VERSION 5.7 ;
BUSBITCHARS "[]" ;
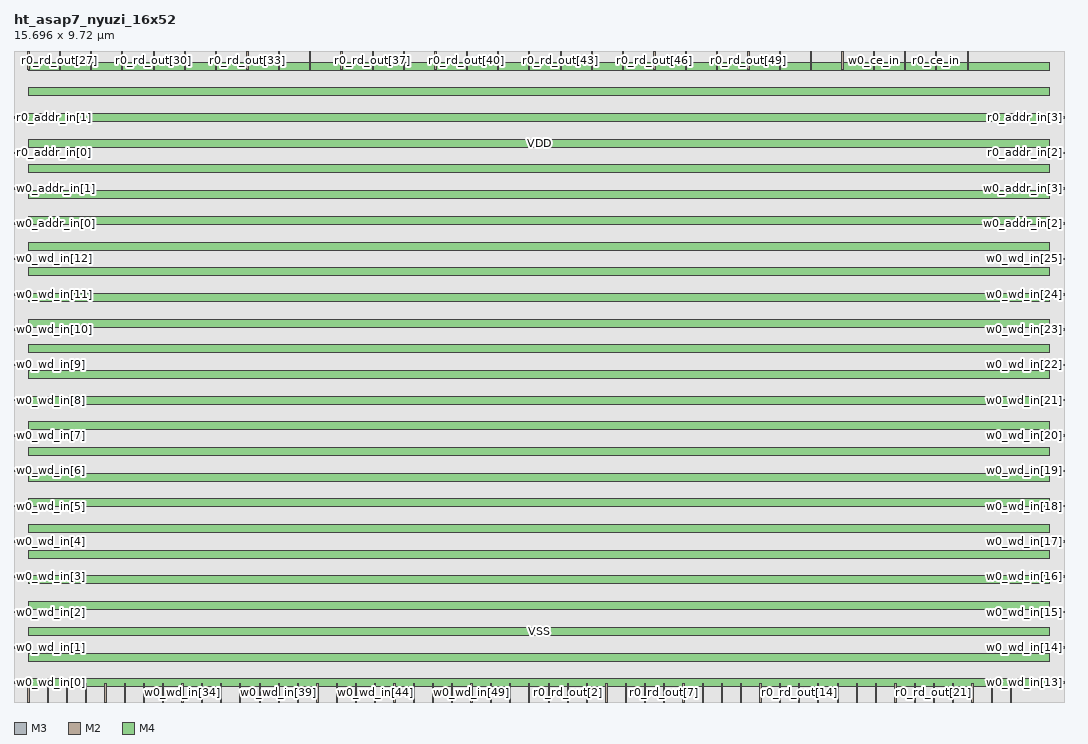
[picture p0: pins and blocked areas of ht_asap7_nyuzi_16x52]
MACRO ht_asap7_nyuzi_16x52
  FOREIGN ht_asap7_nyuzi_16x52 0 0 ;
  SYMMETRY X Y R90 ;
  SIZE 15.696 BY 9.720 ;
  CLASS BLOCK ;
  PIN w0_wd_in[0]
    DIRECTION INPUT ;
    USE SIGNAL ;
    SHAPE ABUTMENT ;
    PORT
      LAYER M3 ;
      RECT 0.000 0.276 0.072 0.300 ;
    END
  END w0_wd_in[0]
  PIN w0_wd_in[1]
    DIRECTION INPUT ;
    USE SIGNAL ;
    SHAPE ABUTMENT ;
    PORT
      LAYER M3 ;
      RECT 0.000 0.804 0.072 0.828 ;
    END
  END w0_wd_in[1]
  PIN w0_wd_in[2]
    DIRECTION INPUT ;
    USE SIGNAL ;
    SHAPE ABUTMENT ;
    PORT
      LAYER M3 ;
      RECT 0.000 1.332 0.072 1.356 ;
    END
  END w0_wd_in[2]
  PIN w0_wd_in[3]
    DIRECTION INPUT ;
    USE SIGNAL ;
    SHAPE ABUTMENT ;
    PORT
      LAYER M3 ;
      RECT 0.000 1.860 0.072 1.884 ;
    END
  END w0_wd_in[3]
  PIN w0_wd_in[4]
    DIRECTION INPUT ;
    USE SIGNAL ;
    SHAPE ABUTMENT ;
    PORT
      LAYER M3 ;
      RECT 0.000 2.388 0.072 2.412 ;
    END
  END w0_wd_in[4]
  PIN w0_wd_in[5]
    DIRECTION INPUT ;
    USE SIGNAL ;
    SHAPE ABUTMENT ;
    PORT
      LAYER M3 ;
      RECT 0.000 2.916 0.072 2.940 ;
    END
  END w0_wd_in[5]
  PIN w0_wd_in[6]
    DIRECTION INPUT ;
    USE SIGNAL ;
    SHAPE ABUTMENT ;
    PORT
      LAYER M3 ;
      RECT 0.000 3.444 0.072 3.468 ;
    END
  END w0_wd_in[6]
  PIN w0_wd_in[7]
    DIRECTION INPUT ;
    USE SIGNAL ;
    SHAPE ABUTMENT ;
    PORT
      LAYER M3 ;
      RECT 0.000 3.972 0.072 3.996 ;
    END
  END w0_wd_in[7]
  PIN w0_wd_in[8]
    DIRECTION INPUT ;
    USE SIGNAL ;
    SHAPE ABUTMENT ;
    PORT
      LAYER M3 ;
      RECT 0.000 4.500 0.072 4.524 ;
    END
  END w0_wd_in[8]
  PIN w0_wd_in[9]
    DIRECTION INPUT ;
    USE SIGNAL ;
    SHAPE ABUTMENT ;
    PORT
      LAYER M3 ;
      RECT 0.000 5.028 0.072 5.052 ;
    END
  END w0_wd_in[9]
  PIN w0_wd_in[10]
    DIRECTION INPUT ;
    USE SIGNAL ;
    SHAPE ABUTMENT ;
    PORT
      LAYER M3 ;
      RECT 0.000 5.556 0.072 5.580 ;
    END
  END w0_wd_in[10]
  PIN w0_wd_in[11]
    DIRECTION INPUT ;
    USE SIGNAL ;
    SHAPE ABUTMENT ;
    PORT
      LAYER M3 ;
      RECT 0.000 6.084 0.072 6.108 ;
    END
  END w0_wd_in[11]
  PIN w0_wd_in[12]
    DIRECTION INPUT ;
    USE SIGNAL ;
    SHAPE ABUTMENT ;
    PORT
      LAYER M3 ;
      RECT 0.000 6.612 0.072 6.636 ;
    END
  END w0_wd_in[12]
  PIN w0_wd_in[13]
    DIRECTION INPUT ;
    USE SIGNAL ;
    SHAPE ABUTMENT ;
    PORT
      LAYER M3 ;
      RECT 15.624 0.276 15.696 0.300 ;
    END
  END w0_wd_in[13]
  PIN w0_wd_in[14]
    DIRECTION INPUT ;
    USE SIGNAL ;
    SHAPE ABUTMENT ;
    PORT
      LAYER M3 ;
      RECT 15.624 0.804 15.696 0.828 ;
    END
  END w0_wd_in[14]
  PIN w0_wd_in[15]
    DIRECTION INPUT ;
    USE SIGNAL ;
    SHAPE ABUTMENT ;
    PORT
      LAYER M3 ;
      RECT 15.624 1.332 15.696 1.356 ;
    END
  END w0_wd_in[15]
  PIN w0_wd_in[16]
    DIRECTION INPUT ;
    USE SIGNAL ;
    SHAPE ABUTMENT ;
    PORT
      LAYER M3 ;
      RECT 15.624 1.860 15.696 1.884 ;
    END
  END w0_wd_in[16]
  PIN w0_wd_in[17]
    DIRECTION INPUT ;
    USE SIGNAL ;
    SHAPE ABUTMENT ;
    PORT
      LAYER M3 ;
      RECT 15.624 2.388 15.696 2.412 ;
    END
  END w0_wd_in[17]
  PIN w0_wd_in[18]
    DIRECTION INPUT ;
    USE SIGNAL ;
    SHAPE ABUTMENT ;
    PORT
      LAYER M3 ;
      RECT 15.624 2.916 15.696 2.940 ;
    END
  END w0_wd_in[18]
  PIN w0_wd_in[19]
    DIRECTION INPUT ;
    USE SIGNAL ;
    SHAPE ABUTMENT ;
    PORT
      LAYER M3 ;
      RECT 15.624 3.444 15.696 3.468 ;
    END
  END w0_wd_in[19]
  PIN w0_wd_in[20]
    DIRECTION INPUT ;
    USE SIGNAL ;
    SHAPE ABUTMENT ;
    PORT
      LAYER M3 ;
      RECT 15.624 3.972 15.696 3.996 ;
    END
  END w0_wd_in[20]
  PIN w0_wd_in[21]
    DIRECTION INPUT ;
    USE SIGNAL ;
    SHAPE ABUTMENT ;
    PORT
      LAYER M3 ;
      RECT 15.624 4.500 15.696 4.524 ;
    END
  END w0_wd_in[21]
  PIN w0_wd_in[22]
    DIRECTION INPUT ;
    USE SIGNAL ;
    SHAPE ABUTMENT ;
    PORT
      LAYER M3 ;
      RECT 15.624 5.028 15.696 5.052 ;
    END
  END w0_wd_in[22]
  PIN w0_wd_in[23]
    DIRECTION INPUT ;
    USE SIGNAL ;
    SHAPE ABUTMENT ;
    PORT
      LAYER M3 ;
      RECT 15.624 5.556 15.696 5.580 ;
    END
  END w0_wd_in[23]
  PIN w0_wd_in[24]
    DIRECTION INPUT ;
    USE SIGNAL ;
    SHAPE ABUTMENT ;
    PORT
      LAYER M3 ;
      RECT 15.624 6.084 15.696 6.108 ;
    END
  END w0_wd_in[24]
  PIN w0_wd_in[25]
    DIRECTION INPUT ;
    USE SIGNAL ;
    SHAPE ABUTMENT ;
    PORT
      LAYER M3 ;
      RECT 15.624 6.612 15.696 6.636 ;
    END
  END w0_wd_in[25]
  PIN w0_wd_in[26]
    DIRECTION INPUT ;
    USE SIGNAL ;
    SHAPE ABUTMENT ;
    PORT
      LAYER M2 ;
      RECT 0.207 0.000 0.225 0.270 ;
    END
  END w0_wd_in[26]
  PIN w0_wd_in[27]
    DIRECTION INPUT ;
    USE SIGNAL ;
    SHAPE ABUTMENT ;
    PORT
      LAYER M2 ;
      RECT 0.495 0.000 0.513 0.270 ;
    END
  END w0_wd_in[27]
  PIN w0_wd_in[28]
    DIRECTION INPUT ;
    USE SIGNAL ;
    SHAPE ABUTMENT ;
    PORT
      LAYER M2 ;
      RECT 0.783 0.000 0.801 0.270 ;
    END
  END w0_wd_in[28]
  PIN w0_wd_in[29]
    DIRECTION INPUT ;
    USE SIGNAL ;
    SHAPE ABUTMENT ;
    PORT
      LAYER M2 ;
      RECT 1.071 0.000 1.089 0.270 ;
    END
  END w0_wd_in[29]
  PIN w0_wd_in[30]
    DIRECTION INPUT ;
    USE SIGNAL ;
    SHAPE ABUTMENT ;
    PORT
      LAYER M2 ;
      RECT 1.359 0.000 1.377 0.270 ;
    END
  END w0_wd_in[30]
  PIN w0_wd_in[31]
    DIRECTION INPUT ;
    USE SIGNAL ;
    SHAPE ABUTMENT ;
    PORT
      LAYER M2 ;
      RECT 1.647 0.000 1.665 0.270 ;
    END
  END w0_wd_in[31]
  PIN w0_wd_in[32]
    DIRECTION INPUT ;
    USE SIGNAL ;
    SHAPE ABUTMENT ;
    PORT
      LAYER M2 ;
      RECT 1.935 0.000 1.953 0.270 ;
    END
  END w0_wd_in[32]
  PIN w0_wd_in[33]
    DIRECTION INPUT ;
    USE SIGNAL ;
    SHAPE ABUTMENT ;
    PORT
      LAYER M2 ;
      RECT 2.223 0.000 2.241 0.270 ;
    END
  END w0_wd_in[33]
  PIN w0_wd_in[34]
    DIRECTION INPUT ;
    USE SIGNAL ;
    SHAPE ABUTMENT ;
    PORT
      LAYER M2 ;
      RECT 2.511 0.000 2.529 0.270 ;
    END
  END w0_wd_in[34]
  PIN w0_wd_in[35]
    DIRECTION INPUT ;
    USE SIGNAL ;
    SHAPE ABUTMENT ;
    PORT
      LAYER M2 ;
      RECT 2.799 0.000 2.817 0.270 ;
    END
  END w0_wd_in[35]
  PIN w0_wd_in[36]
    DIRECTION INPUT ;
    USE SIGNAL ;
    SHAPE ABUTMENT ;
    PORT
      LAYER M2 ;
      RECT 3.087 0.000 3.105 0.270 ;
    END
  END w0_wd_in[36]
  PIN w0_wd_in[37]
    DIRECTION INPUT ;
    USE SIGNAL ;
    SHAPE ABUTMENT ;
    PORT
      LAYER M2 ;
      RECT 3.375 0.000 3.393 0.270 ;
    END
  END w0_wd_in[37]
  PIN w0_wd_in[38]
    DIRECTION INPUT ;
    USE SIGNAL ;
    SHAPE ABUTMENT ;
    PORT
      LAYER M2 ;
      RECT 3.663 0.000 3.681 0.270 ;
    END
  END w0_wd_in[38]
  PIN w0_wd_in[39]
    DIRECTION INPUT ;
    USE SIGNAL ;
    SHAPE ABUTMENT ;
    PORT
      LAYER M2 ;
      RECT 3.951 0.000 3.969 0.270 ;
    END
  END w0_wd_in[39]
  PIN w0_wd_in[40]
    DIRECTION INPUT ;
    USE SIGNAL ;
    SHAPE ABUTMENT ;
    PORT
      LAYER M2 ;
      RECT 4.239 0.000 4.257 0.270 ;
    END
  END w0_wd_in[40]
  PIN w0_wd_in[41]
    DIRECTION INPUT ;
    USE SIGNAL ;
    SHAPE ABUTMENT ;
    PORT
      LAYER M2 ;
      RECT 4.527 0.000 4.545 0.270 ;
    END
  END w0_wd_in[41]
  PIN w0_wd_in[42]
    DIRECTION INPUT ;
    USE SIGNAL ;
    SHAPE ABUTMENT ;
    PORT
      LAYER M2 ;
      RECT 4.815 0.000 4.833 0.270 ;
    END
  END w0_wd_in[42]
  PIN w0_wd_in[43]
    DIRECTION INPUT ;
    USE SIGNAL ;
    SHAPE ABUTMENT ;
    PORT
      LAYER M2 ;
      RECT 5.103 0.000 5.121 0.270 ;
    END
  END w0_wd_in[43]
  PIN w0_wd_in[44]
    DIRECTION INPUT ;
    USE SIGNAL ;
    SHAPE ABUTMENT ;
    PORT
      LAYER M2 ;
      RECT 5.391 0.000 5.409 0.270 ;
    END
  END w0_wd_in[44]
  PIN w0_wd_in[45]
    DIRECTION INPUT ;
    USE SIGNAL ;
    SHAPE ABUTMENT ;
    PORT
      LAYER M2 ;
      RECT 5.679 0.000 5.697 0.270 ;
    END
  END w0_wd_in[45]
  PIN w0_wd_in[46]
    DIRECTION INPUT ;
    USE SIGNAL ;
    SHAPE ABUTMENT ;
    PORT
      LAYER M2 ;
      RECT 5.967 0.000 5.985 0.270 ;
    END
  END w0_wd_in[46]
  PIN w0_wd_in[47]
    DIRECTION INPUT ;
    USE SIGNAL ;
    SHAPE ABUTMENT ;
    PORT
      LAYER M2 ;
      RECT 6.255 0.000 6.273 0.270 ;
    END
  END w0_wd_in[47]
  PIN w0_wd_in[48]
    DIRECTION INPUT ;
    USE SIGNAL ;
    SHAPE ABUTMENT ;
    PORT
      LAYER M2 ;
      RECT 6.543 0.000 6.561 0.270 ;
    END
  END w0_wd_in[48]
  PIN w0_wd_in[49]
    DIRECTION INPUT ;
    USE SIGNAL ;
    SHAPE ABUTMENT ;
    PORT
      LAYER M2 ;
      RECT 6.831 0.000 6.849 0.270 ;
    END
  END w0_wd_in[49]
  PIN w0_wd_in[50]
    DIRECTION INPUT ;
    USE SIGNAL ;
    SHAPE ABUTMENT ;
    PORT
      LAYER M2 ;
      RECT 7.119 0.000 7.137 0.270 ;
    END
  END w0_wd_in[50]
  PIN w0_wd_in[51]
    DIRECTION INPUT ;
    USE SIGNAL ;
    SHAPE ABUTMENT ;
    PORT
      LAYER M2 ;
      RECT 7.407 0.000 7.425 0.270 ;
    END
  END w0_wd_in[51]
  PIN r0_rd_out[0]
    DIRECTION OUTPUT ;
    USE SIGNAL ;
    SHAPE ABUTMENT ;
    PORT
      LAYER M2 ;
      RECT 7.695 0.000 7.713 0.270 ;
    END
  END r0_rd_out[0]
  PIN r0_rd_out[1]
    DIRECTION OUTPUT ;
    USE SIGNAL ;
    SHAPE ABUTMENT ;
    PORT
      LAYER M2 ;
      RECT 7.983 0.000 8.001 0.270 ;
    END
  END r0_rd_out[1]
  PIN r0_rd_out[2]
    DIRECTION OUTPUT ;
    USE SIGNAL ;
    SHAPE ABUTMENT ;
    PORT
      LAYER M2 ;
      RECT 8.271 0.000 8.289 0.270 ;
    END
  END r0_rd_out[2]
  PIN r0_rd_out[3]
    DIRECTION OUTPUT ;
    USE SIGNAL ;
    SHAPE ABUTMENT ;
    PORT
      LAYER M2 ;
      RECT 8.559 0.000 8.577 0.270 ;
    END
  END r0_rd_out[3]
  PIN r0_rd_out[4]
    DIRECTION OUTPUT ;
    USE SIGNAL ;
    SHAPE ABUTMENT ;
    PORT
      LAYER M2 ;
      RECT 8.847 0.000 8.865 0.270 ;
    END
  END r0_rd_out[4]
  PIN r0_rd_out[5]
    DIRECTION OUTPUT ;
    USE SIGNAL ;
    SHAPE ABUTMENT ;
    PORT
      LAYER M2 ;
      RECT 9.135 0.000 9.153 0.270 ;
    END
  END r0_rd_out[5]
  PIN r0_rd_out[6]
    DIRECTION OUTPUT ;
    USE SIGNAL ;
    SHAPE ABUTMENT ;
    PORT
      LAYER M2 ;
      RECT 9.423 0.000 9.441 0.270 ;
    END
  END r0_rd_out[6]
  PIN r0_rd_out[7]
    DIRECTION OUTPUT ;
    USE SIGNAL ;
    SHAPE ABUTMENT ;
    PORT
      LAYER M2 ;
      RECT 9.711 0.000 9.729 0.270 ;
    END
  END r0_rd_out[7]
  PIN r0_rd_out[8]
    DIRECTION OUTPUT ;
    USE SIGNAL ;
    SHAPE ABUTMENT ;
    PORT
      LAYER M2 ;
      RECT 9.999 0.000 10.017 0.270 ;
    END
  END r0_rd_out[8]
  PIN r0_rd_out[9]
    DIRECTION OUTPUT ;
    USE SIGNAL ;
    SHAPE ABUTMENT ;
    PORT
      LAYER M2 ;
      RECT 10.287 0.000 10.305 0.270 ;
    END
  END r0_rd_out[9]
  PIN r0_rd_out[10]
    DIRECTION OUTPUT ;
    USE SIGNAL ;
    SHAPE ABUTMENT ;
    PORT
      LAYER M2 ;
      RECT 10.575 0.000 10.593 0.270 ;
    END
  END r0_rd_out[10]
  PIN r0_rd_out[11]
    DIRECTION OUTPUT ;
    USE SIGNAL ;
    SHAPE ABUTMENT ;
    PORT
      LAYER M2 ;
      RECT 10.863 0.000 10.881 0.270 ;
    END
  END r0_rd_out[11]
  PIN r0_rd_out[12]
    DIRECTION OUTPUT ;
    USE SIGNAL ;
    SHAPE ABUTMENT ;
    PORT
      LAYER M2 ;
      RECT 11.151 0.000 11.169 0.270 ;
    END
  END r0_rd_out[12]
  PIN r0_rd_out[13]
    DIRECTION OUTPUT ;
    USE SIGNAL ;
    SHAPE ABUTMENT ;
    PORT
      LAYER M2 ;
      RECT 11.439 0.000 11.457 0.270 ;
    END
  END r0_rd_out[13]
  PIN r0_rd_out[14]
    DIRECTION OUTPUT ;
    USE SIGNAL ;
    SHAPE ABUTMENT ;
    PORT
      LAYER M2 ;
      RECT 11.727 0.000 11.745 0.270 ;
    END
  END r0_rd_out[14]
  PIN r0_rd_out[15]
    DIRECTION OUTPUT ;
    USE SIGNAL ;
    SHAPE ABUTMENT ;
    PORT
      LAYER M2 ;
      RECT 12.015 0.000 12.033 0.270 ;
    END
  END r0_rd_out[15]
  PIN r0_rd_out[16]
    DIRECTION OUTPUT ;
    USE SIGNAL ;
    SHAPE ABUTMENT ;
    PORT
      LAYER M2 ;
      RECT 12.303 0.000 12.321 0.270 ;
    END
  END r0_rd_out[16]
  PIN r0_rd_out[17]
    DIRECTION OUTPUT ;
    USE SIGNAL ;
    SHAPE ABUTMENT ;
    PORT
      LAYER M2 ;
      RECT 12.591 0.000 12.609 0.270 ;
    END
  END r0_rd_out[17]
  PIN r0_rd_out[18]
    DIRECTION OUTPUT ;
    USE SIGNAL ;
    SHAPE ABUTMENT ;
    PORT
      LAYER M2 ;
      RECT 12.879 0.000 12.897 0.270 ;
    END
  END r0_rd_out[18]
  PIN r0_rd_out[19]
    DIRECTION OUTPUT ;
    USE SIGNAL ;
    SHAPE ABUTMENT ;
    PORT
      LAYER M2 ;
      RECT 13.167 0.000 13.185 0.270 ;
    END
  END r0_rd_out[19]
  PIN r0_rd_out[20]
    DIRECTION OUTPUT ;
    USE SIGNAL ;
    SHAPE ABUTMENT ;
    PORT
      LAYER M2 ;
      RECT 13.455 0.000 13.473 0.270 ;
    END
  END r0_rd_out[20]
  PIN r0_rd_out[21]
    DIRECTION OUTPUT ;
    USE SIGNAL ;
    SHAPE ABUTMENT ;
    PORT
      LAYER M2 ;
      RECT 13.743 0.000 13.761 0.270 ;
    END
  END r0_rd_out[21]
  PIN r0_rd_out[22]
    DIRECTION OUTPUT ;
    USE SIGNAL ;
    SHAPE ABUTMENT ;
    PORT
      LAYER M2 ;
      RECT 14.031 0.000 14.049 0.270 ;
    END
  END r0_rd_out[22]
  PIN r0_rd_out[23]
    DIRECTION OUTPUT ;
    USE SIGNAL ;
    SHAPE ABUTMENT ;
    PORT
      LAYER M2 ;
      RECT 14.319 0.000 14.337 0.270 ;
    END
  END r0_rd_out[23]
  PIN r0_rd_out[24]
    DIRECTION OUTPUT ;
    USE SIGNAL ;
    SHAPE ABUTMENT ;
    PORT
      LAYER M2 ;
      RECT 14.607 0.000 14.625 0.270 ;
    END
  END r0_rd_out[24]
  PIN r0_rd_out[25]
    DIRECTION OUTPUT ;
    USE SIGNAL ;
    SHAPE ABUTMENT ;
    PORT
      LAYER M2 ;
      RECT 14.895 0.000 14.913 0.270 ;
    END
  END r0_rd_out[25]
  PIN r0_rd_out[26]
    DIRECTION OUTPUT ;
    USE SIGNAL ;
    SHAPE ABUTMENT ;
    PORT
      LAYER M2 ;
      RECT 0.207 9.450 0.225 9.720 ;
    END
  END r0_rd_out[26]
  PIN r0_rd_out[27]
    DIRECTION OUTPUT ;
    USE SIGNAL ;
    SHAPE ABUTMENT ;
    PORT
      LAYER M2 ;
      RECT 0.675 9.450 0.693 9.720 ;
    END
  END r0_rd_out[27]
  PIN r0_rd_out[28]
    DIRECTION OUTPUT ;
    USE SIGNAL ;
    SHAPE ABUTMENT ;
    PORT
      LAYER M2 ;
      RECT 1.143 9.450 1.161 9.720 ;
    END
  END r0_rd_out[28]
  PIN r0_rd_out[29]
    DIRECTION OUTPUT ;
    USE SIGNAL ;
    SHAPE ABUTMENT ;
    PORT
      LAYER M2 ;
      RECT 1.611 9.450 1.629 9.720 ;
    END
  END r0_rd_out[29]
  PIN r0_rd_out[30]
    DIRECTION OUTPUT ;
    USE SIGNAL ;
    SHAPE ABUTMENT ;
    PORT
      LAYER M2 ;
      RECT 2.079 9.450 2.097 9.720 ;
    END
  END r0_rd_out[30]
  PIN r0_rd_out[31]
    DIRECTION OUTPUT ;
    USE SIGNAL ;
    SHAPE ABUTMENT ;
    PORT
      LAYER M2 ;
      RECT 2.547 9.450 2.565 9.720 ;
    END
  END r0_rd_out[31]
  PIN r0_rd_out[32]
    DIRECTION OUTPUT ;
    USE SIGNAL ;
    SHAPE ABUTMENT ;
    PORT
      LAYER M2 ;
      RECT 3.015 9.450 3.033 9.720 ;
    END
  END r0_rd_out[32]
  PIN r0_rd_out[33]
    DIRECTION OUTPUT ;
    USE SIGNAL ;
    SHAPE ABUTMENT ;
    PORT
      LAYER M2 ;
      RECT 3.483 9.450 3.501 9.720 ;
    END
  END r0_rd_out[33]
  PIN r0_rd_out[34]
    DIRECTION OUTPUT ;
    USE SIGNAL ;
    SHAPE ABUTMENT ;
    PORT
      LAYER M2 ;
      RECT 3.951 9.450 3.969 9.720 ;
    END
  END r0_rd_out[34]
  PIN r0_rd_out[35]
    DIRECTION OUTPUT ;
    USE SIGNAL ;
    SHAPE ABUTMENT ;
    PORT
      LAYER M2 ;
      RECT 4.419 9.450 4.437 9.720 ;
    END
  END r0_rd_out[35]
  PIN r0_rd_out[36]
    DIRECTION OUTPUT ;
    USE SIGNAL ;
    SHAPE ABUTMENT ;
    PORT
      LAYER M2 ;
      RECT 4.887 9.450 4.905 9.720 ;
    END
  END r0_rd_out[36]
  PIN r0_rd_out[37]
    DIRECTION OUTPUT ;
    USE SIGNAL ;
    SHAPE ABUTMENT ;
    PORT
      LAYER M2 ;
      RECT 5.355 9.450 5.373 9.720 ;
    END
  END r0_rd_out[37]
  PIN r0_rd_out[38]
    DIRECTION OUTPUT ;
    USE SIGNAL ;
    SHAPE ABUTMENT ;
    PORT
      LAYER M2 ;
      RECT 5.823 9.450 5.841 9.720 ;
    END
  END r0_rd_out[38]
  PIN r0_rd_out[39]
    DIRECTION OUTPUT ;
    USE SIGNAL ;
    SHAPE ABUTMENT ;
    PORT
      LAYER M2 ;
      RECT 6.291 9.450 6.309 9.720 ;
    END
  END r0_rd_out[39]
  PIN r0_rd_out[40]
    DIRECTION OUTPUT ;
    USE SIGNAL ;
    SHAPE ABUTMENT ;
    PORT
      LAYER M2 ;
      RECT 6.759 9.450 6.777 9.720 ;
    END
  END r0_rd_out[40]
  PIN r0_rd_out[41]
    DIRECTION OUTPUT ;
    USE SIGNAL ;
    SHAPE ABUTMENT ;
    PORT
      LAYER M2 ;
      RECT 7.227 9.450 7.245 9.720 ;
    END
  END r0_rd_out[41]
  PIN r0_rd_out[42]
    DIRECTION OUTPUT ;
    USE SIGNAL ;
    SHAPE ABUTMENT ;
    PORT
      LAYER M2 ;
      RECT 7.695 9.450 7.713 9.720 ;
    END
  END r0_rd_out[42]
  PIN r0_rd_out[43]
    DIRECTION OUTPUT ;
    USE SIGNAL ;
    SHAPE ABUTMENT ;
    PORT
      LAYER M2 ;
      RECT 8.163 9.450 8.181 9.720 ;
    END
  END r0_rd_out[43]
  PIN r0_rd_out[44]
    DIRECTION OUTPUT ;
    USE SIGNAL ;
    SHAPE ABUTMENT ;
    PORT
      LAYER M2 ;
      RECT 8.631 9.450 8.649 9.720 ;
    END
  END r0_rd_out[44]
  PIN r0_rd_out[45]
    DIRECTION OUTPUT ;
    USE SIGNAL ;
    SHAPE ABUTMENT ;
    PORT
      LAYER M2 ;
      RECT 9.099 9.450 9.117 9.720 ;
    END
  END r0_rd_out[45]
  PIN r0_rd_out[46]
    DIRECTION OUTPUT ;
    USE SIGNAL ;
    SHAPE ABUTMENT ;
    PORT
      LAYER M2 ;
      RECT 9.567 9.450 9.585 9.720 ;
    END
  END r0_rd_out[46]
  PIN r0_rd_out[47]
    DIRECTION OUTPUT ;
    USE SIGNAL ;
    SHAPE ABUTMENT ;
    PORT
      LAYER M2 ;
      RECT 10.035 9.450 10.053 9.720 ;
    END
  END r0_rd_out[47]
  PIN r0_rd_out[48]
    DIRECTION OUTPUT ;
    USE SIGNAL ;
    SHAPE ABUTMENT ;
    PORT
      LAYER M2 ;
      RECT 10.503 9.450 10.521 9.720 ;
    END
  END r0_rd_out[48]
  PIN r0_rd_out[49]
    DIRECTION OUTPUT ;
    USE SIGNAL ;
    SHAPE ABUTMENT ;
    PORT
      LAYER M2 ;
      RECT 10.971 9.450 10.989 9.720 ;
    END
  END r0_rd_out[49]
  PIN r0_rd_out[50]
    DIRECTION OUTPUT ;
    USE SIGNAL ;
    SHAPE ABUTMENT ;
    PORT
      LAYER M2 ;
      RECT 11.439 9.450 11.457 9.720 ;
    END
  END r0_rd_out[50]
  PIN r0_rd_out[51]
    DIRECTION OUTPUT ;
    USE SIGNAL ;
    SHAPE ABUTMENT ;
    PORT
      LAYER M2 ;
      RECT 11.907 9.450 11.925 9.720 ;
    END
  END r0_rd_out[51]
  PIN w0_addr_in[0]
    DIRECTION INPUT ;
    USE SIGNAL ;
    SHAPE ABUTMENT ;
    PORT
      LAYER M3 ;
      RECT 0.000 7.140 0.072 7.164 ;
    END
  END w0_addr_in[0]
  PIN w0_addr_in[1]
    DIRECTION INPUT ;
    USE SIGNAL ;
    SHAPE ABUTMENT ;
    PORT
      LAYER M3 ;
      RECT 0.000 7.668 0.072 7.692 ;
    END
  END w0_addr_in[1]
  PIN w0_addr_in[2]
    DIRECTION INPUT ;
    USE SIGNAL ;
    SHAPE ABUTMENT ;
    PORT
      LAYER M3 ;
      RECT 15.624 7.140 15.696 7.164 ;
    END
  END w0_addr_in[2]
  PIN w0_addr_in[3]
    DIRECTION INPUT ;
    USE SIGNAL ;
    SHAPE ABUTMENT ;
    PORT
      LAYER M3 ;
      RECT 15.624 7.668 15.696 7.692 ;
    END
  END w0_addr_in[3]
  PIN r0_addr_in[0]
    DIRECTION INPUT ;
    USE SIGNAL ;
    SHAPE ABUTMENT ;
    PORT
      LAYER M3 ;
      RECT 0.000 8.196 0.072 8.220 ;
    END
  END r0_addr_in[0]
  PIN r0_addr_in[1]
    DIRECTION INPUT ;
    USE SIGNAL ;
    SHAPE ABUTMENT ;
    PORT
      LAYER M3 ;
      RECT 0.000 8.724 0.072 8.748 ;
    END
  END r0_addr_in[1]
  PIN r0_addr_in[2]
    DIRECTION INPUT ;
    USE SIGNAL ;
    SHAPE ABUTMENT ;
    PORT
      LAYER M3 ;
      RECT 15.624 8.196 15.696 8.220 ;
    END
  END r0_addr_in[2]
  PIN r0_addr_in[3]
    DIRECTION INPUT ;
    USE SIGNAL ;
    SHAPE ABUTMENT ;
    PORT
      LAYER M3 ;
      RECT 15.624 8.724 15.696 8.748 ;
    END
  END r0_addr_in[3]
  PIN w0_we_in
    DIRECTION INPUT ;
    USE SIGNAL ;
    SHAPE ABUTMENT ;
    PORT
      LAYER M2 ;
      RECT 12.375 9.450 12.393 9.720 ;
    END
  END w0_we_in
  PIN w0_ce_in
    DIRECTION INPUT ;
    USE SIGNAL ;
    SHAPE ABUTMENT ;
    PORT
      LAYER M2 ;
      RECT 12.843 9.450 12.861 9.720 ;
    END
  END w0_ce_in
  PIN w0_clk
    DIRECTION INPUT ;
    USE SIGNAL ;
    SHAPE ABUTMENT ;
    PORT
      LAYER M2 ;
      RECT 13.311 9.450 13.329 9.720 ;
    END
  END w0_clk
  PIN r0_ce_in
    DIRECTION INPUT ;
    USE SIGNAL ;
    SHAPE ABUTMENT ;
    PORT
      LAYER M2 ;
      RECT 13.779 9.450 13.797 9.720 ;
    END
  END r0_ce_in
  PIN r0_clk
    DIRECTION INPUT ;
    USE SIGNAL ;
    SHAPE ABUTMENT ;
    PORT
      LAYER M2 ;
      RECT 14.247 9.450 14.265 9.720 ;
    END
  END r0_clk
  PIN VSS
    DIRECTION INOUT ;
    USE GROUND ;
    PORT
      LAYER M4 ;
      RECT 0.216 0.228 15.480 0.348 ;
      RECT 0.216 0.996 15.480 1.116 ;
      RECT 0.216 1.764 15.480 1.884 ;
      RECT 0.216 2.532 15.480 2.652 ;
      RECT 0.216 3.300 15.480 3.420 ;
      RECT 0.216 4.068 15.480 4.188 ;
      RECT 0.216 4.836 15.480 4.956 ;
      RECT 0.216 5.604 15.480 5.724 ;
      RECT 0.216 6.372 15.480 6.492 ;
      RECT 0.216 7.140 15.480 7.260 ;
      RECT 0.216 7.908 15.480 8.028 ;
      RECT 0.216 8.676 15.480 8.796 ;
      RECT 0.216 9.444 15.480 9.564 ;
    END
  END VSS
  PIN VDD
    DIRECTION INOUT ;
    USE POWER ;
    PORT
      LAYER M4 ;
      RECT 0.216 0.612 15.480 0.732 ;
      RECT 0.216 1.380 15.480 1.500 ;
      RECT 0.216 2.148 15.480 2.268 ;
      RECT 0.216 2.916 15.480 3.036 ;
      RECT 0.216 3.684 15.480 3.804 ;
      RECT 0.216 4.452 15.480 4.572 ;
      RECT 0.216 5.220 15.480 5.340 ;
      RECT 0.216 5.988 15.480 6.108 ;
      RECT 0.216 6.756 15.480 6.876 ;
      RECT 0.216 7.524 15.480 7.644 ;
      RECT 0.216 8.292 15.480 8.412 ;
      RECT 0.216 9.060 15.480 9.180 ;
    END
  END VDD
  OBS
    LAYER M1 ;
    RECT 0 0 15.696 9.720 ;
    LAYER M2 ;
    RECT 0 0 15.696 9.720 ;
    LAYER M3 ;
    RECT 0 0 15.696 9.720 ;
    LAYER M4 ;
    RECT 0 0 15.696 9.720 ;
  END
END ht_asap7_nyuzi_16x52

END LIBRARY
